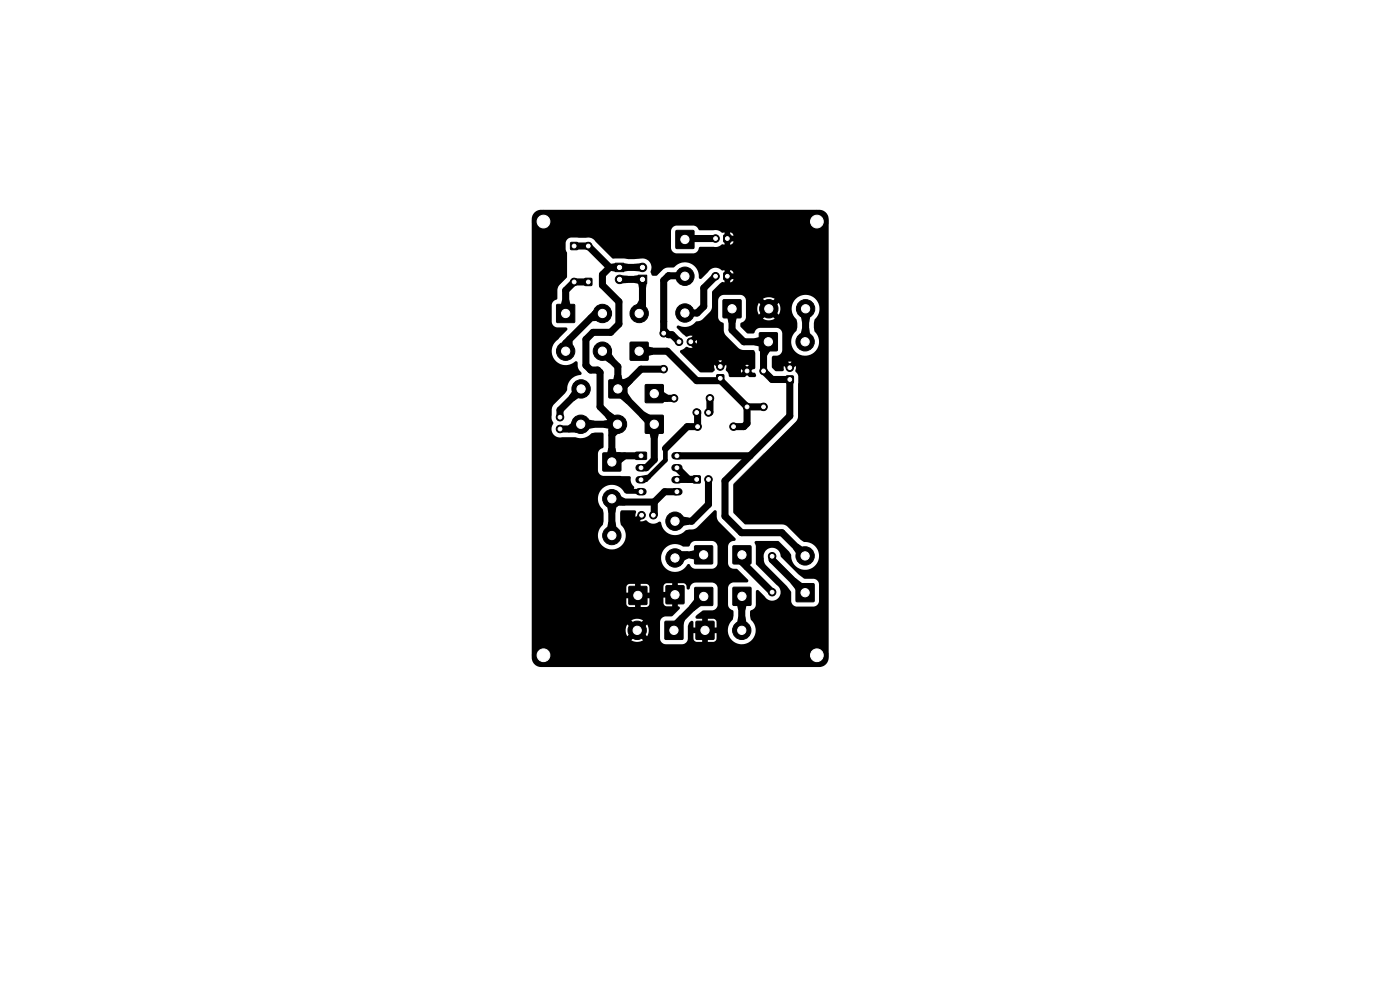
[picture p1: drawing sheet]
<svg xmlns="http://www.w3.org/2000/svg" width="297mm" height="210mm" viewBox="0 0 297 210" stroke-linecap="round" stroke-linejoin="round" font-family="sans-serif">
<g fill="#000" stroke="#000" stroke-width=".21">
<path d="M121.1 51.5h1.4v1.4h-1.4zM130.5 55.8h1.8v1.8h-1.8zM143.4 48.9h3.8v3.8h-3.8zM153.6 49.9h1.4v1.4h-1.4zM153.6 57.9h1.4v1.4h-1.4zM118.1 64.6h3.8v3.8h-3.8zM124.1 59.1h1.4v1.4h-1.4zM133.7 72.6h3.8v3.8h-3.8zM135.4 58.4h1.8v1.8h-1.8zM153.4 63.6h3.8v3.8h-3.8zM161.1 70.6h3.8v3.8h-3.8zM127.9 96.1h3.8v3.8h-3.8z"/>
<path d="M129.2 80.6h3.8v3.8h-3.8zM134.9 96l2.1-.1 .2 .2v1.2l-.3 .2h-2l-.1-.3zM136.9 81.6h3.8v3.8h-3.8zM136.9 88.1h3.8v3.8h-3.8zM152.1 79.5h1.4v1.5h-1.4zM166.8 79.8h1.5v1.4h-1.5zM147.1 101h1.4v1.4h-1.4zM147.4 115.8h3.7v3.8h-3.7zM155.5 115.8h3.8v3.8h-3.8zM133.4 124.4h3.8v3.8h-3.8zM141.3 124.3h3.8v3.7h-3.8zM141.1 131.8h3.8v3.8h-3.8z"/>
<path d="M147.4 124.7h3.8v3.7h-3.8zM147.7 131.8h3.7v3.8h-3.7zM155.5 124.6h3.8v3.8h-3.8zM168.9 123.8h3.8v3.8h-3.8z"/>
<circle cx="115.3" cy="47" r="2.35"/>
<circle cx="121.8" cy="59.8" r=".8"/>
<circle cx="124.8" cy="52.2" r=".8"/>
<circle cx="131.4" cy="59.3" r=".9"/>
<circle cx="136.3" cy="56.7" r=".9"/>
<circle cx="145.3" cy="58.6" r="1.95"/>
<circle cx="151.8" cy="50.6" r=".8"/>
<circle cx="151.8" cy="58.6" r=".8"/>
<circle cx="173.3" cy="47" r="2.35"/>
<circle cx="120" cy="74.5" r="1.95"/>
<circle cx="127.8" cy="74.5" r="1.95"/>
<circle cx="127.8" cy="66.5" r="1.95"/>
<circle cx="135.6" cy="66.5" r="1.95"/>
<circle cx="140.8" cy="70.7" r=".8"/>
<circle cx="140.8" cy="78.3" r=".8"/>
<circle cx="144" cy="72.5" r=".8"/>
<circle cx="145.3" cy="66.4" r="1.95"/>
<circle cx="146.5" cy="72.5" r=".8"/>
<circle cx="152.8" cy="77.7" r=".8"/>
<circle cx="158.5" cy="78.7" r=".8"/>
<circle cx="162" cy="78.7" r=".8"/>
<circle cx="163.1" cy="65.5" r="1.95"/>
<circle cx="167.5" cy="78" r=".8"/>
<circle cx="170.8" cy="72.5" r="1.95"/>
<circle cx="170.9" cy="65.5" r="1.95"/>
<circle cx="118.8" cy="88.5" r=".8"/>
<circle cx="118.8" cy="91" r=".8"/>
<circle cx="123.2" cy="90" r="1.95"/>
<circle cx="123.3" cy="82.5" r="1.95"/>
<circle cx="131" cy="90" r="1.95"/>
<circle cx="143" cy="84.5" r=".8"/>
<circle cx="147.8" cy="87.5" r=".8"/>
<circle cx="148" cy="90.5" r=".8"/>
<circle cx="150.3" cy="87.5" r=".8"/>
<circle cx="150.6" cy="84.5" r=".8"/>
<circle cx="155.6" cy="90.5" r=".8"/>
<circle cx="158.5" cy="86.3" r=".8"/>
<circle cx="162" cy="86.3" r=".8"/>
<circle cx="129.8" cy="113.6" r="1.95"/>
<circle cx="129.8" cy="105.8" r="1.95"/>
<circle cx="136.1" cy="109.3" r=".8"/>
<circle cx="138.6" cy="109.3" r=".8"/>
<circle cx="143.2" cy="118.4" r="1.95"/>
<circle cx="143.2" cy="110.6" r="1.95"/>
<circle cx="150.3" cy="101.7" r=".8"/>
<circle cx="163.8" cy="118" r=".8"/>
<circle cx="170.8" cy="117.9" r="1.95"/>
<circle cx="115.3" cy="139" r="2.35"/>
<circle cx="135.2" cy="133.7" r="1.95"/>
<circle cx="157.4" cy="133.7" r="1.95"/>
<circle cx="163.8" cy="125.6" r=".8"/>
<circle cx="173.3" cy="139" r="2.35"/>
</g>
<path d="M135.6 99.2h.8M143.2 99.2h.8M143.2 96.7h.8M135.6 101.8h.8M135.6 104.3h.8M143.2 101.8h.8M143.2 104.3h.8" fill="none" stroke="#000" stroke-width="1.6"/>
<g fill="none" stroke="#000" stroke-width="1.5">
<path d="M121.8 52.2h3l4.5 4.5M124.8 59.8h-3l-1.8 1.8v4.9M129.3 56.7l-1.5 1.6v2.2l3.5 3.5v4.8l-1.8 1.7h-3.7l-1.5 1.5v5.5l1 1h1.5l.5 .5v7.3l3.7 3.7M129.3 56.7h7M131.4 59.3h4.9v6.5l-.7 .7M141.9 58.6l-.1-.1-1 1v10.5l1 1h.7l1.5 1.5M141.9 58.5h3.4M151.8 58.6l-2.5 2.5v3.9l-1.4 1.4h-2.6M151.8 50.6h-6.3l-.2 .2M127.8 74.5l3.3 3.3v5l7.2 7.2h.5v7.5l-1.7 1.7h-1.1M127.8 66.5h-1.5l-6.3 6.3v1.7M135.6 74.5h6l6.2 6.3h5.1l5.6 5.5"/>
<path d="M140.8 78.3h-4.8l-4.2 4.2h-.7M155.3 65.5v4.5l2.5 2.5h5.2l-1 1v5.2l1.8 1.8h3.8v7.8l-13.8 13.7v7.5l3.5 3.5h8.6l4.9 4.9M170.9 65.5l-.1 7M123.3 82.5l-4.5 4.5v1.5M131 90l-1.2 1.2v6.8l1.3-1.3h4.9M131 90h-7.8l-1 1h-3.4M138.8 83.5l1 1h3.2M143.6 96.7h15.5M143.6 99.2l2.5 2.5M148 87.5v3h-2.2l-4.6 4.6M150.6 84.5l-.1 3M158.5 86.3v3.5l-.7 .7h-2.2"/>
<path d="M158.5 86.3h3.5M138.8 106.5h-8.3l-.7-.7v7.8M138.8 106.5v2.6l-.2 .2M143.6 104.3h-2.6l-2.2 2.2M147.8 101.7l-4.2 .1M149.3 117.7h-5.4l-.7 .7M150.3 101.7v5.3l-3.6 3.6h-3.5M157.4 117.7v1.5l6.4 6.4M163.8 118v.7l7 7M149.3 126.5l-6.3 6.3v.9M157.4 126.5v7.2"/>
</g>
<path d="M141.2 95.1v2.5l-4.2 4.2h-1" fill="none" stroke="#000" stroke-width="1"/>
<g fill="#000">
<path d="M129.6 56l.9-.2 .9 .9-.9 .9-.9-.1zM131.6 58.4l1.6 .1v1.5l-1.6 .1a2.26 2.26 0 0 1 0-1.7zM131.4 56.7l.9-.9 .9 .2v1.5l-.9 .1zM134.5 58.5l.9-.1 .9 .9-.9 .9-.9-.2zM134.5 56l1.6-.1a2.26 2.26 0 0 1 0 1.7l-1.6-.1zM136.3 59.3l.9 .9-.2 .9h-1.5l-.1-.9zM113.4 45.1l.7-.5 .7-.1h59a2 2 0 0 1 2 2v93a2 2 0 0 1-2 2h-59a2 2 0 0 1-2-2v-5.9h19.9l.1 .8 .3 .6 1.2-1.2a.87 .87 0 0 0 .8 .8l-1.1 1.3a2.44 2.44 0 0 0 2.4-.1l-1.1-1.2a.87 .87 0 0 0 .7-.9l1.3 1.2a2.44 2.44 0 0 0 0-2.4l-1.3 1.1a.87 .87 0 0 0-.8-.8l.9-.9h3.9v3.7a1.25 1.25 0 0 0 1.2 1.1h3.6a1.24 1.24 0 0 0 1.1-1.2v-2.6l.2-.7 .4-.4 .3-.1 .3 .2v1.2l1.8 .1a.87 .87 0 0 0 0 1.1h-1.8v1.2l.2 .4 .4 .3h1.3v-1.8a.87 .87 0 0 0 1.2-.1v1.9h1.1l.4-.2 .3-.4v-1.3h-1.8a.87 .87 0 0 0 0-1.2h1.8v-1.1l-.1-.5-.5-.2h-1.2l-.1 1.7a.87 .87 0 0 0-1.1 .1v-1.8h-1.1a.35 .35 0 0 1-.3-.3 .35 .35 0 0 1 0-.3l1.5-1.2h2.1a1.25 1.25 0 0 0 1-1.2v-3.7a1.25 1.25 0 0 0-1.1-1h-3.7a1.48 1.48 0 0 0-1.1 1.4 .35 .35 0 0 1-.4 0 .35 .35 0 0 1-.3-.3 .8 .8 0 0 0-.7-1h-1.1v1.8a.87 .87 0 0 0-1.2 0v-1.8h-1.2l-.4 .2-.2 .4-.1 1.3h1.8a.87 .87 0 0 0 .1 1.2h-1.9v1.1l.2 .4 .4 .3h1.3v-1.8a.87 .87 0 0 0 1.2 0l.1 1.8a.35 .35 0 0 1 .3 .2 .35 .35 0 0 1-.1 .4l-1.5 1.5-1.4 .1a1.24 1.24 0 0 0-1.2 1.1h-3.9l.3-.3a2.44 2.44 0 0 0-2.5 0l1.2 1.2a.87 .87 0 0 0-.8 .9l-1.2-1.2-.4 1.1h-19.9v-9h20.1v1.1l1.7 .1a.87 .87 0 0 0 .1 1.1h-1.8v1.2l.1 .4 .5 .3h1.2l.1-1.8a.87 .87 0 0 0 1.1-.1v1.9h1.2l.4-.2 .3-.4v-1.3h-1.8a.87 .87 0 0 0 0-1.2h1.8v-1.1l-.2-.5-.4-.2h-1.3v1.7a.87 .87 0 0 0-1.2 .1v-1.8h-1.4l-.4 .7h-20.1v-6.4h27.4a3 3 0 0 0 2.3 3 3 3 0 0 0 3.5-1.5l.4 .1a1.26 1.26 0 0 0 1.1 .9l3.6-.1a1.24 1.24 0 0 0 1.1-1.1v-3.7a1.25 1.25 0 0 0-1.2-1.1l-3.6 .1a1.67 1.67 0 0 0-1.1 1l-1.4 .1a2.96 2.96 0 0 0-4.7 2.3h-27.4v-29.8h4.2l.4 1.5a1.82 1.82 0 0 0-.1 2.1 1.82 1.82 0 0 0 2 .8h2.8a3.3 3.3 0 0 0 3.5-.9l2.1-.1 .3 .1v2.9l-.2 .3a1.23 1.23 0 0 0-1 1.1l.1 3.7a1.25 1.25 0 0 0 1.1 1.1h5.5l.3 .2v.2a2.72 2.72 0 0 0 .8 2l-.2 .3h1.3l.3 .2a.4 .4 0 0 0-.4 .4 .4 .4 0 0 0 .2 .4h-2.8a1.35 1.35 0 0 1-1-.9 2.99 2.99 0 0 0-4.4 0 2.99 2.99 0 0 0 .3 4.4l.1 2.3-.1 .8a2.98 2.98 0 0 0-.2 4.4 2.98 2.98 0 0 0 4.4-.2 2.98 2.98 0 0 0-.4-4.3l-.1-2.3 .1-.6h2.9a.57 .57 0 0 1 .2 .9l.1 .5 .6-.6 .3-.1a.4 .4 0 0 0 0 .6 .4 .4 0 0 0 .6 0l-.1 .3-.6 .6 .5 .1 .8-.2a2.11 2.11 0 0 0 2.9 .2l.2 .1a3.1 3.1 0 0 0 2.2 2.7 3.1 3.1 0 0 0 3.3-1l1.5-.1 .6-.3 3.8-3.7a.35 .35 0 0 1 .3-.1 .35 .35 0 0 1 .2 .4l.1 1.2 .2 .7 3.7 3.7a.4 .4 0 0 1 0 .4 .4 .4 0 0 1-.5 .2 1.25 1.25 0 0 0-1.1 1.1l.1 3.7a1.25 1.25 0 0 0 1.1 1.1h.8l2.3 2.3a.35 .35 0 0 1 0 .3 .35 .35 0 0 1-.3 .2l-2.9 .1a1.25 1.25 0 0 0-1.1 1.1l.1 3.7a2.21 2.21 0 0 0 1.1 1.2l-.1 1.7a3 3 0 0 0-.3 4.4 3 3 0 0 0 4.4 0 3 3 0 0 0-.4-4.4l-.1-1.5 .3-.4a1.24 1.24 0 0 0 1-1.1v-3l.3-.2 .2 .1 1.3 1.3a1.81 1.81 0 0 0 2.9 .4 1.81 1.81 0 0 0-.4-2.8l-4.3-4.4v-1.8h1.6l.1 1.2 .2 .6 4.6 4.6 .9 1.1v2.1a1.25 1.25 0 0 0 1.2 1.2h3.6a1.24 1.24 0 0 0 1.2-1.2l-.1-3.7a1.25 1.25 0 0 0-1.1-1l-2.1-.1-1.1-.9-3.7-3.6a1.86 1.86 0 0 0-1.7-2 1.86 1.86 0 0 0-2 1.7h-1.6l-.1-2.3a.45 .45 0 0 1-.2-.5 .45 .45 0 0 1 .3-.3h4.7l2.3 2.2 .4 .7a2.98 2.98 0 0 0 3 3.1 2.98 2.98 0 0 0 3-3.1 2.98 2.98 0 0 0-3.3-2.8l-3.8-3.5-.7-.2h-7.9l-2.5-2.6v-5.9l13.5-13.7 .2-.6 .1-8.5-.3-.8a.69 .69 0 0 1-.3-1v-.5l-.7 .6-.2 .1a.4 .4 0 0 0-.1-.6 .4 .4 0 0 0-.5 0 .4 .4 0 0 0-.1 .6l-.3-.1-.6-.6v.8l-.2 .3h-1.4l-.9-.6-.1-1.3h3.5l.4 .4 .3-.4h-4.2l.1-1.2 .3-.1 .8-.1a1.25 1.25 0 0 0 1.1-1.1v-2h1.8a2.98 2.98 0 0 0 4.2 2.9 2.98 2.98 0 0 0 .8-5l-.1-1.7a2.26 2.26 0 0 1 .8-1.6 2.97 2.97 0 0 0-1.1-3.9 2.97 2.97 0 0 0-4 .8 2.97 2.97 0 0 0 .6 4.1l.1 1.5-.2 .9a2.94 2.94 0 0 0-1.1 2h-1.8v-1.6a1.24 1.24 0 0 0-1.2-1.2l-3.7 .1a2.15 2.15 0 0 0-1.2 1.1l-1.5-.1-1.3-1.3v-.7l.2-.2a1.23 1.23 0 0 0 1-1.1v-1.9h2.3l.1 .8 .3 .6 1.2-1.2a.87 .87 0 0 0 .9 .8l-1.2 1.2a2.44 2.44 0 0 0 2.5 0l-1.2-1.2a.87 .87 0 0 0 .8-.9l1.2 1.2a2.44 2.44 0 0 0 0-2.5l-1.2 1.2a.87 .87 0 0 0-.9-.8l1.2-1.2a2.44 2.44 0 0 0-2.5 0l1.2 1.2a.87 .87 0 0 0-.8 .9l-1.2-1.3-.4 1.2h-2.3v-1.7a1.24 1.24 0 0 0-1.2-1.2l-3.7 .1a1.25 1.25 0 0 0-1.1 1.1l.1 3.7a2.15 2.15 0 0 0 1.1 1.2l.1 1.7 .2 .7 2.8 2.8 .9 .4 2.3 .1 .2 .1 .2 .5v3.1l-.1 .3h-.4l-.4 .4 .4 .4h.5l.2 .6-.2 .3h-1.1l-.6-.5-.6 .5h-3.1l-.2-.3-.2-.6-.4-.5h3.2v.5l.4-.5 .5 .1a.4 .4 0 0 0 .6 .3 .4 .4 0 0 0 0-.7 .4 .4 0 0 0-.6 .3h-.5l-.4-.3v.3h-3.2l.1-1.1h4l.4 .3 .4-.3-4.9-.1-.6 .6h-.3a.4 .4 0 0 0 0-.5 .4 .4 0 0 0-.6 0 .4 .4 0 0 0 0 .5h-.3l-.6-.6v1.1l-.4 .5h-2.6l-2.6-2.5h6.4l.4 .4 .4-.4h-7.2l-1.7-1.8a.5 .5 0 0 1 .5-.6l.8-.5 .8 .2 .5-.1-.6-.6v-.3a.4 .4 0 0 0 .4 .1 .4 .4 0 0 0 .3-.4h.4l.4 .4v-.8l-.4 .4-.4-.1a.4 .4 0 0 0-.7-.2v-.3l.6-.6-.5-.1-.9 .2-1.8-1.7a.39 .39 0 0 1 0-.6 .39 .39 0 0 1 .6 .1 3.6 3.6 0 0 0 3.5-1l.7-.1 .6-.4 1.8-1.9 .2-.7 .1-3.4 1.9-1.9 1.9 .1 .5-.4 .1-.3h-.7v.7h-1.2v-1.4l.2 .2a.4 .4 0 0 0 .6 .2 .4 .4 0 0 0 0-.6 .4 .4 0 0 0-.6 .2h-.2v-.5h1.9l-.1-.3-.6-.4v.7h-1.2v-.7h-.6a1.82 1.82 0 0 0-2.9 .4l-1.5 1.5a.35 .35 0 0 1-.3-.1 .35 .35 0 0 1-.1-.3 2.96 2.96 0 0 0-1.9-2.9 2.96 2.96 0 0 0-3.3 .7l-2.1 .3-1.7 1.6h-.9l-.2-.3a1.28 1.28 0 0 1 0-1.3 1.9 1.9 0 0 0-2.2-2.1l-2.6 .2-1.1-.2h-2.4l-3.6-3.6a1.83 1.83 0 0 0-2-.8h-3.1a1.24 1.24 0 0 0-1.2 1.2v1.3l.3 .8v5l-1.9 2.1-.2 .7v1.8l-.1 .2a1.3 1.3 0 0 0-1.1 1.2l.1 3.7a1.25 1.25 0 0 0 1.1 1.1h1.8l.4 .2-.1 .3-1.8 1.9a2.97 2.97 0 0 0-.9 4.3 2.97 2.97 0 0 0 4.4 .5l.3-.1 .2 .3 .1 1.2 .8 1-.1 .4a3.2 3.2 0 0 0-3 3.3l-.4 .6-2.6 2.6-.2 .6-.1 1.8h-4.2v-39.4h29.5l.1 3.7a1.26 1.26 0 0 0 1.1 1.1l3.6-.1a1.41 1.41 0 0 0 1.2-1.2l.3-.1h3.3l.9-.3a.65 .65 0 0 1 .9-.2h1.3l.3-.2 .3-.4-.7-.1v.7h-1.2v-1.4l.2 .2a.4 .4 0 0 0 .6 .2 .4 .4 0 0 0 0-.6 .4 .4 0 0 0-.6 .2h-.2v-.5h1.9l-.1-.3-.6-.4v.7h-1.2v-.7h-.6a1.86 1.86 0 0 0-1.8-.5h-2.8l-.3-.1a1.26 1.26 0 0 0-1.1-.9l-3.7 .1a1.25 1.25 0 0 0-1.1 1.1h-29.5v-2.8zM120.4 71.3l1.1 1.1v.9l-1.5 1.2-.4-1.9zM119.3 63.6h1.5l.2 1-1 1.9-1-1.9zM124.7 67.1l1.2-.9 1.9 .3-1.1 1.6h-1zM127.8 74.5l1.9 .5 .7 1.1-1.1 1-1-.7zM130.3 79.6h1.5l.3 1-1 1.9-1-1.9z"/>
<path d="M135.5 63.7h1.5v1.4l-1.4 1.4-.6-1.8zM135.6 74.5l1.9-1 1 .2v1.5l-1 .3zM155.3 65.5l1 1.9-.3 1.1-1.5-.1-.2-1zM160.1 71.8l1-.3 1.9 1-1.9 1-1-.2zM163 72.5l.4 2-.7 .9h-1.5l.1-1zM170.9 65.5l1 1.7-.3 1.2h-1.5l-.2-1.2zM170.2 69.6h1.5l.2 1.3-1.1 1.6-.9-1.7zM120.5 90.2l.8-.5 1.9 .3-1.2 1.5-1.4 .2zM121.4 83l1.9-.5-.5 1.9-1.1 .7-1-1.1zM123.2 90l1.7-1 1.2 .2v1.5l-1.2 .3zM128.1 89.3l1.2-.3 1.7 1-1.7 1-1.2-.2zM128.4 88.4l1.1-1 1 .7 .5 1.9-1.9-.5z"/>
<path d="M129.1 95.1h1.5l.2 1-1 1.9-1-1.9zM129.4 91.1l1.6-1.1 .2 1.9-.7 .6h-1.4zM131.1 82.5l1.9 .7 1 1.4-1.1 1.1-1.4-1.3zM131.6 96.1l1.1-.2v1.5l-1 .8-1.9-.2zM132.1 80.6l1.1-.6 1.1 1.1-1.3 1.2-1.9 .2zM135.6 88.4l1.1-1.1 1.3 .8 .8 1.9-1.9-.3zM138.8 90l1 1.9-.3 1.1-1.5-.1-.2-1zM138.8 83.5l2-.4 .9 .7v1.4h-1zM129.8 105.8l1 1.7-.3 1.2h-1.5l-.2-1.2zM129.1 110.7h1.5l.2 1.2-1 1.7-1-1.7zM129.8 105.8l1.9-.6 .9 .6v1.4h-1.4zM135.8 101l1.6-.3 .7 .7-1 .8-1.1-.4z"/>
<path d="M143.2 118.4l1.4-1.4h1.4v1.5l-1 .5zM143.2 110.6l1.6-1 1.3 .2v1.5l-1.3 .3zM146.3 117l1-.3 2 1-2 1-1-.2zM157.4 117.7l1.9 1.9-1.3 1.3-.9-1.3zM169.2 115.3l1.1 .8 .5 1.8-1.9-.4-.7-1.1zM144.2 130.5l1.1 1.1-.4 1-1.9 1.1 .1-1.9zM147.3 127.1l2-.6-.5 2-1.6 1.1-1-1zM157.4 126.5l1 2-.3 .9-1.5 .1-.2-1.1zM156.6 130.8h1.5l.3 1.3-1 1.6-1-1.6zM167.7 123.7l1.1-1.1 1.5 1.2 .5 1.9-1.9-.5z"/>
</g>
<g fill="#fff" stroke="#fff" stroke-width=".21">
<circle cx="145.3" cy="50.8" r=".87"/>
<circle cx="145.3" cy="58.6" r=".87"/>
<circle cx="145.3" cy="66.4" r=".87"/>
<circle cx="121.8" cy="52.2" r=".4"/>
<circle cx="121.8" cy="59.8" r=".4"/>
<circle cx="146.6" cy="72.5" r=".4"/>
<circle cx="144" cy="72.5" r=".4"/>
<circle cx="143" cy="133.7" r=".87"/>
<circle cx="135.2" cy="133.7" r=".87"/>
<circle cx="162" cy="78.7" r=".4"/>
<circle cx="162" cy="86.3" r=".4"/>
<circle cx="149.3" cy="117.7" r=".87"/>
<circle cx="167.6" cy="80.5" r=".4"/>
<circle cx="167.5" cy="78" r=".4"/>
<circle cx="154.3" cy="50.6" r=".4"/>
<circle cx="151.8" cy="50.6" r=".4"/>
<circle cx="136" cy="96.7" r=".4"/>
<circle cx="136" cy="99.2" r=".4"/>
<circle cx="136" cy="101.8" r=".4"/>
<circle cx="136" cy="104.3" r=".4"/>
<circle cx="143.6" cy="104.3" r=".4"/>
<circle cx="143.6" cy="101.8" r=".4"/>
<circle cx="143.6" cy="99.2" r=".4"/>
<circle cx="143.6" cy="96.7" r=".4"/>
<circle cx="173.3" cy="47" r="1.35"/>
<circle cx="158.5" cy="86.3" r=".4"/>
<circle cx="158.5" cy="78.7" r=".4"/>
<circle cx="138.8" cy="90" r=".87"/>
<circle cx="131" cy="90" r=".87"/>
<circle cx="123.2" cy="90" r=".87"/>
<circle cx="147.8" cy="101.7" r=".4"/>
<circle cx="150.3" cy="101.7" r=".4"/>
<circle cx="157.4" cy="117.7" r=".87"/>
<circle cx="143" cy="84.5" r=".4"/>
<circle cx="150.6" cy="84.5" r=".4"/>
<circle cx="163.8" cy="125.6" r=".4"/>
<circle cx="163.8" cy="118" r=".4"/>
<circle cx="120" cy="66.5" r=".87"/>
<circle cx="127.8" cy="66.5" r=".87"/>
<circle cx="135.6" cy="66.5" r=".87"/>
<circle cx="154.3" cy="58.6" r=".4"/>
<circle cx="151.8" cy="58.6" r=".4"/>
<circle cx="138.8" cy="83.5" r=".87"/>
<circle cx="148" cy="90.5" r=".4"/>
<circle cx="155.6" cy="90.5" r=".4"/>
<circle cx="149.6" cy="133.7" r=".87"/>
<circle cx="157.4" cy="133.7" r=".87"/>
<circle cx="136.3" cy="59.3" r=".45"/>
<circle cx="136.3" cy="56.7" r=".45"/>
<circle cx="140.8" cy="78.3" r=".4"/>
<circle cx="140.8" cy="70.7" r=".4"/>
<circle cx="124.8" cy="59.8" r=".4"/>
<circle cx="124.8" cy="52.2" r=".4"/>
<circle cx="149.3" cy="126.5" r=".87"/>
<circle cx="129.8" cy="98" r=".87"/>
<circle cx="129.8" cy="105.8" r=".87"/>
<circle cx="129.8" cy="113.6" r=".87"/>
<circle cx="135.3" cy="126.3" r=".87"/>
<circle cx="115.3" cy="47" r="1.35"/>
<circle cx="138.6" cy="109.3" r=".4"/>
<circle cx="136.1" cy="109.3" r=".4"/>
<circle cx="118.8" cy="88.5" r=".4"/>
<circle cx="118.8" cy="91" r=".4"/>
<circle cx="150.3" cy="87.5" r=".4"/>
<circle cx="147.8" cy="87.5" r=".4"/>
<circle cx="155.3" cy="65.5" r=".87"/>
<circle cx="163.1" cy="65.5" r=".87"/>
<circle cx="170.9" cy="65.5" r=".87"/>
<circle cx="173.3" cy="139" r="1.35"/>
<circle cx="143.2" cy="126.2" r=".87"/>
<circle cx="143.2" cy="118.4" r=".87"/>
<circle cx="143.2" cy="110.6" r=".87"/>
<circle cx="115.3" cy="139" r="1.35"/>
<circle cx="135.6" cy="74.5" r=".87"/>
<circle cx="120" cy="74.5" r=".87"/>
<circle cx="127.8" cy="74.5" r=".87"/>
<circle cx="152.8" cy="80.3" r=".4"/>
<circle cx="152.8" cy="77.8" r=".4"/>
<circle cx="170.8" cy="125.7" r=".87"/>
<circle cx="170.8" cy="117.9" r=".87"/>
<circle cx="131.1" cy="82.5" r=".87"/>
<circle cx="123.3" cy="82.5" r=".87"/>
<circle cx="157.4" cy="126.5" r=".87"/>
<circle cx="163" cy="72.5" r=".87"/>
<circle cx="170.8" cy="72.5" r=".87"/>
<circle cx="131.4" cy="56.7" r=".45"/>
<circle cx="131.4" cy="59.3" r=".45"/>
</g>
</svg>
